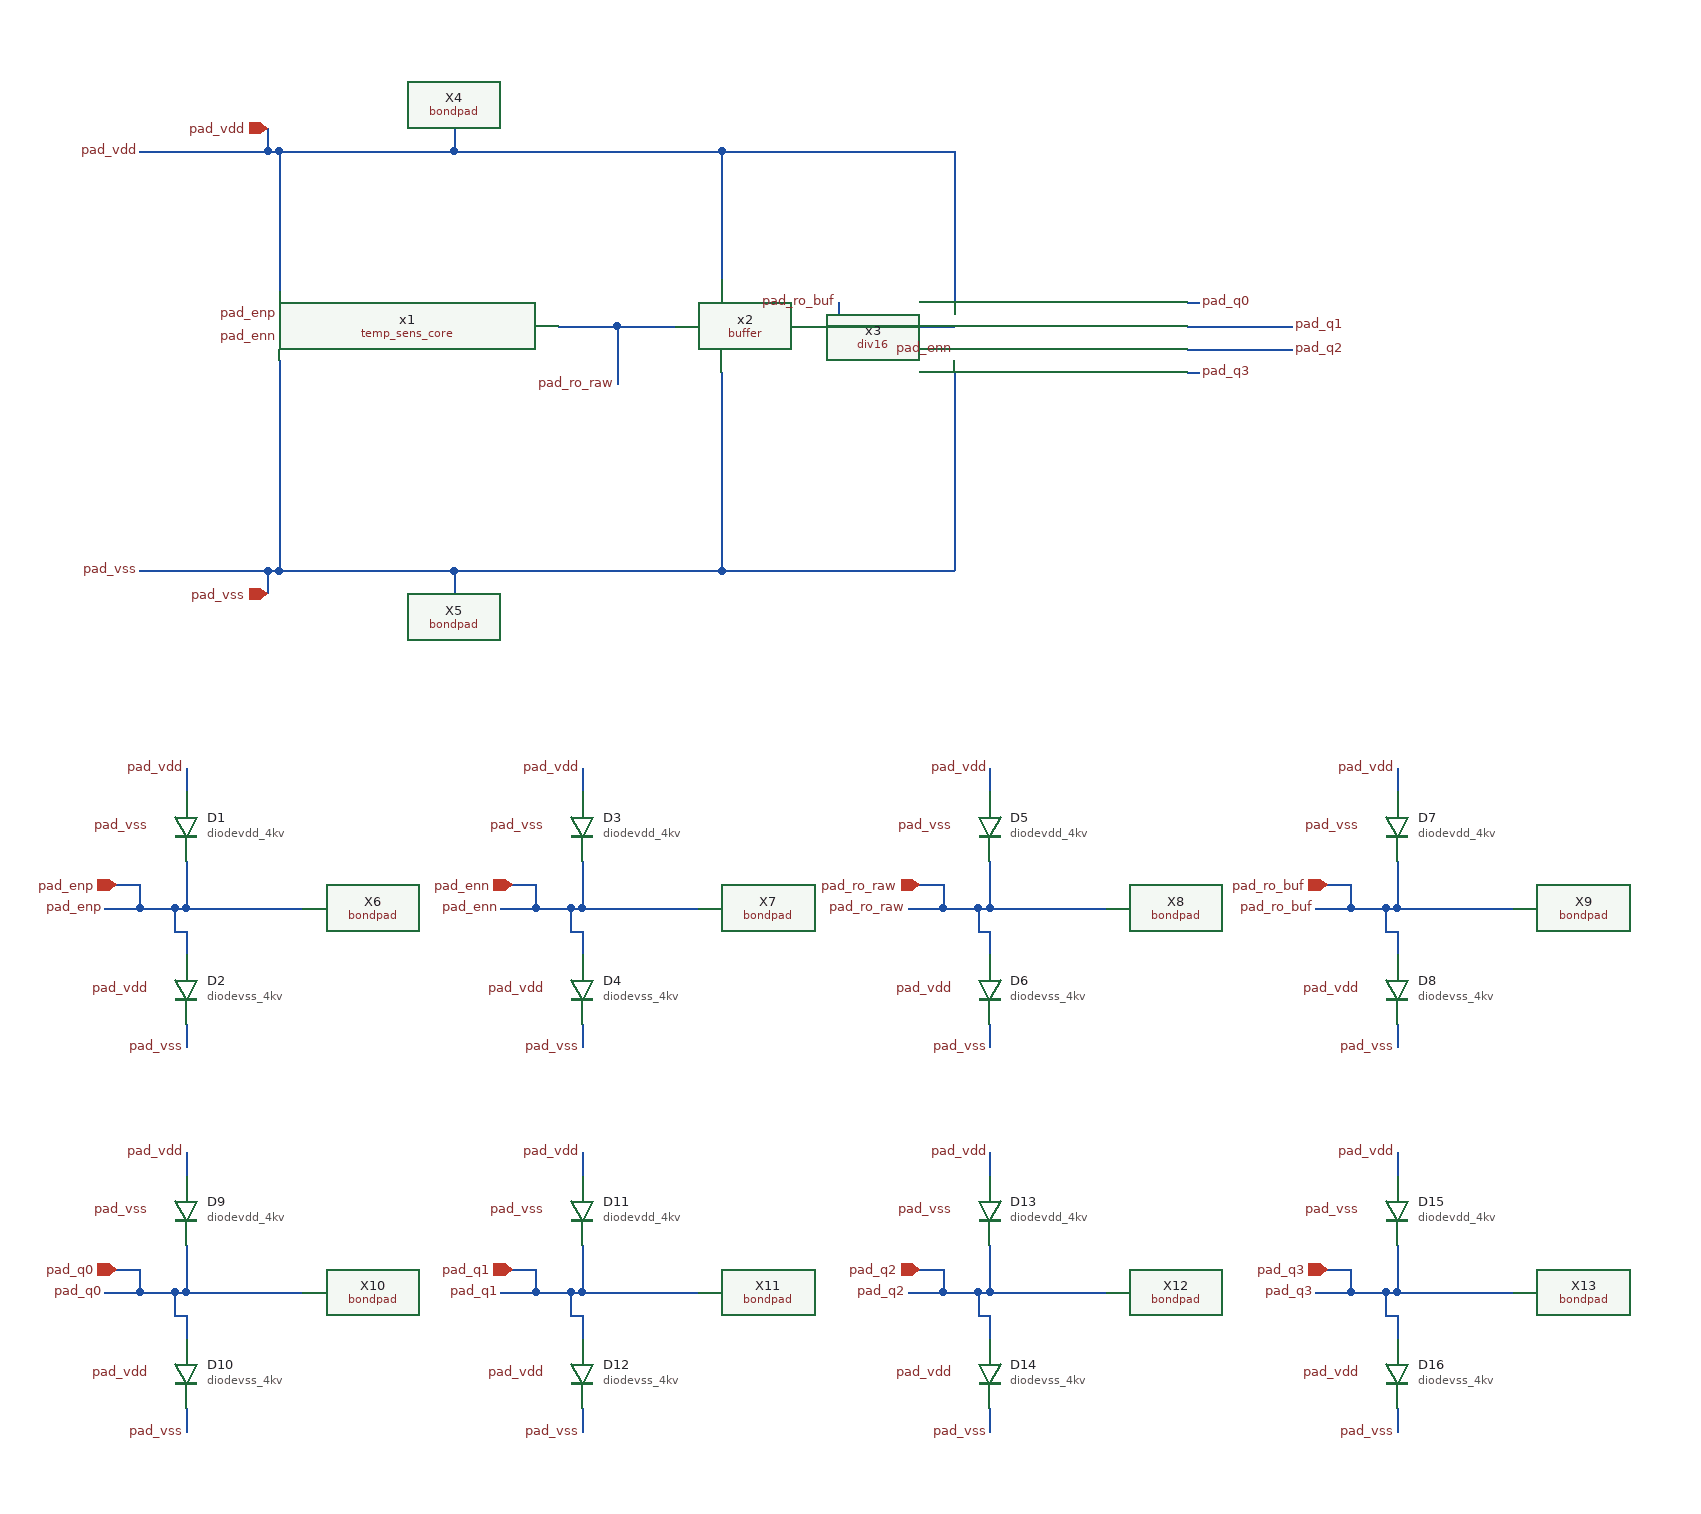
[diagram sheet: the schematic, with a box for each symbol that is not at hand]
v {xschem version=3.4.8RC file_version=1.3}
G {}
K {}
V {}
S {}
F {}
E {}
N 540 -990 590 -990 {lab=pad_ro_raw}
N 1030 -1010 1040 -1010 {lab=pad_q0}
N 1030 -950 1040 -950 {lab=pad_q3}
N 1030 -990 1120 -990 {lab=pad_q1}
N 1030 -970 1120 -970 {lab=pad_q2}
N 540 -990 540 -940 {lab=pad_ro_raw}
N 490 -990 540 -990 {lab=pad_ro_raw}
N 730 -990 830 -990 {lab=pad_ro_buf}
N 250 -1140 250 -1020 {lab=pad_vdd}
N 240 -1140 250 -1140 {lab=pad_vdd}
N 630 -1140 630 -1030 {lab=pad_vdd}
N 400 -1140 630 -1140 {lab=pad_vdd}
N 830 -1140 830 -1010 {lab=pad_vdd}
N 630 -1140 830 -1140 {lab=pad_vdd}
N 400 -780 400 -760 {lab=pad_vss}
N 250 -780 400 -780 {lab=pad_vss}
N 400 -1160 400 -1140 {lab=pad_vdd}
N 250 -1140 400 -1140 {lab=pad_vdd}
N 240 -1160 240 -1140 {lab=pad_vdd}
N 130 -1140 240 -1140 {lab=pad_vdd}
N 250 -960 250 -780 {lab=pad_vss}
N 240 -780 250 -780 {lab=pad_vss}
N 630 -950 630 -780 {lab=pad_vss}
N 400 -780 630 -780 {lab=pad_vss}
N 830 -950 830 -780 {lab=pad_vss}
N 630 -780 830 -780 {lab=pad_vss}
N 170 -490 270 -490 {lab=pad_enp}
N 170 -530 170 -490 {lab=pad_enp}
N 160 -490 170 -490 {lab=pad_enp}
N 170 -610 170 -590 {lab=pad_vdd}
N 170 -390 170 -370 {lab=pad_vss}
N 170 -470 170 -450 {lab=pad_enp}
N 160 -470 170 -470 {lab=pad_enp}
N 160 -490 160 -470 {lab=pad_enp}
N 130 -490 160 -490 {lab=pad_enp}
N 110 -510 130 -510 {lab=pad_enp}
N 130 -510 130 -490 {lab=pad_enp}
N 100 -490 130 -490 {lab=pad_enp}
N 510 -490 610 -490 {lab=pad_enn}
N 510 -530 510 -490 {lab=pad_enn}
N 500 -490 510 -490 {lab=pad_enn}
N 510 -610 510 -590 {lab=pad_vdd}
N 510 -390 510 -370 {lab=pad_vss}
N 510 -470 510 -450 {lab=pad_enn}
N 500 -470 510 -470 {lab=pad_enn}
N 500 -490 500 -470 {lab=pad_enn}
N 470 -490 500 -490 {lab=pad_enn}
N 450 -510 470 -510 {lab=pad_enn}
N 470 -510 470 -490 {lab=pad_enn}
N 440 -490 470 -490 {lab=pad_enn}
N 860 -490 960 -490 {lab=pad_ro_raw}
N 860 -530 860 -490 {lab=pad_ro_raw}
N 850 -490 860 -490 {lab=pad_ro_raw}
N 860 -610 860 -590 {lab=pad_vdd}
N 860 -390 860 -370 {lab=pad_vss}
N 860 -470 860 -450 {lab=pad_ro_raw}
N 850 -470 860 -470 {lab=pad_ro_raw}
N 850 -490 850 -470 {lab=pad_ro_raw}
N 820 -490 850 -490 {lab=pad_ro_raw}
N 800 -510 820 -510 {lab=pad_ro_raw}
N 820 -510 820 -490 {lab=pad_ro_raw}
N 790 -490 820 -490 {lab=pad_ro_raw}
N 1210 -490 1310 -490 {lab=pad_ro_buf}
N 1210 -530 1210 -490 {lab=pad_ro_buf}
N 1200 -490 1210 -490 {lab=pad_ro_buf}
N 1210 -610 1210 -590 {lab=pad_vdd}
N 1210 -390 1210 -370 {lab=pad_vss}
N 1210 -470 1210 -450 {lab=pad_ro_buf}
N 1200 -470 1210 -470 {lab=pad_ro_buf}
N 1200 -490 1200 -470 {lab=pad_ro_buf}
N 1170 -490 1200 -490 {lab=pad_ro_buf}
N 1150 -510 1170 -510 {lab=pad_ro_buf}
N 1170 -510 1170 -490 {lab=pad_ro_buf}
N 1140 -490 1170 -490 {lab=pad_ro_buf}
N 170 -160 270 -160 {lab=pad_q0}
N 170 -200 170 -160 {lab=pad_q0}
N 160 -160 170 -160 {lab=pad_q0}
N 170 -280 170 -260 {lab=pad_vdd}
N 170 -60 170 -40 {lab=pad_vss}
N 170 -140 170 -120 {lab=pad_q0}
N 160 -140 170 -140 {lab=pad_q0}
N 160 -160 160 -140 {lab=pad_q0}
N 130 -160 160 -160 {lab=pad_q0}
N 110 -180 130 -180 {lab=pad_q0}
N 130 -180 130 -160 {lab=pad_q0}
N 100 -160 130 -160 {lab=pad_q0}
N 510 -160 610 -160 {lab=pad_q1}
N 510 -200 510 -160 {lab=pad_q1}
N 500 -160 510 -160 {lab=pad_q1}
N 510 -280 510 -260 {lab=pad_vdd}
N 510 -60 510 -40 {lab=pad_vss}
N 510 -140 510 -120 {lab=pad_q1}
N 500 -140 510 -140 {lab=pad_q1}
N 500 -160 500 -140 {lab=pad_q1}
N 470 -160 500 -160 {lab=pad_q1}
N 450 -180 470 -180 {lab=pad_q1}
N 470 -180 470 -160 {lab=pad_q1}
N 440 -160 470 -160 {lab=pad_q1}
N 860 -160 960 -160 {lab=pad_q2}
N 860 -200 860 -160 {lab=pad_q2}
N 850 -160 860 -160 {lab=pad_q2}
N 860 -280 860 -260 {lab=pad_vdd}
N 860 -60 860 -40 {lab=pad_vss}
N 860 -140 860 -120 {lab=pad_q2}
N 850 -140 860 -140 {lab=pad_q2}
N 850 -160 850 -140 {lab=pad_q2}
N 820 -160 850 -160 {lab=pad_q2}
N 800 -180 820 -180 {lab=pad_q2}
N 820 -180 820 -160 {lab=pad_q2}
N 790 -160 820 -160 {lab=pad_q2}
N 1210 -160 1310 -160 {lab=pad_enp}
N 1210 -200 1210 -160 {lab=pad_enp}
N 1200 -160 1210 -160 {lab=pad_enp}
N 1210 -280 1210 -260 {lab=pad_vdd}
N 1210 -60 1210 -40 {lab=pad_vss}
N 1210 -140 1210 -120 {lab=pad_enp}
N 1200 -140 1210 -140 {lab=pad_enp}
N 1200 -160 1200 -140 {lab=pad_enp}
N 1170 -160 1200 -160 {lab=pad_enp}
N 1150 -180 1170 -180 {lab=pad_enp}
N 1170 -180 1170 -160 {lab=pad_enp}
N 1140 -160 1170 -160 {lab=pad_enp}
N 730 -1010 730 -990 {lab=pad_ro_buf}
N 690 -990 730 -990 {lab=pad_ro_buf}
N 240 -780 240 -760 {lab=pad_vss}
N 130 -780 240 -780 {lab=pad_vss}
C {TSENSE8490-main/schematic/xschem/analog/temp-sens-core/temp_sens_core.sym} 370 -1000 0 0 {name=x1 lstarv=0.46u}
C {TSENSE8490-main/schematic/xschem/analog/buffer/buffer.sym} 470 -870 0 0 {name=x2}
C {TSENSE8490-main/schematic/xschem/digital/div16/xschem/div16.sym} 930 -950 0 0 {name=x3}
C {lab_pin.sym} 100 -490 0 0 {name=p13 sig_type=std_logic lab=pad_enp
}
C {lab_pin.sym} 440 -490 0 0 {name=p14 sig_type=std_logic lab=pad_enn
}
C {lab_pin.sym} 250 -1000 0 0 {name=p19 sig_type=std_logic lab=pad_enp
}
C {lab_pin.sym} 250 -980 0 0 {name=p20 sig_type=std_logic lab=pad_enn
}
C {lab_pin.sym} 830 -970 0 0 {name=p11 sig_type=std_logic lab=pad_enn
}
C {sg13cmos5l_pr/bondpad.sym} 400 -1200 0 0 {name=X4
model=bondpad
spiceprefix=X
size=150u
shape=0
padtype=0
}
C {sg13cmos5l_pr/bondpad.sym} 400 -720 2 0 {name=X5
model=bondpad
spiceprefix=X
size=150u
shape=0
padtype=0
}
C {sg13cmos5l_pr/bondpad.sym} 270 -530 0 0 {name=X6
model=bondpad
spiceprefix=X
size=150u
shape=0
padtype=0
}
C {sg13cmos5l_pr/bondpad.sym} 610 -530 0 0 {name=X7
model=bondpad
spiceprefix=X
size=150u
shape=0
padtype=0
}
C {sg13cmos5l_pr/bondpad.sym} 960 -530 0 0 {name=X8
model=bondpad
spiceprefix=X
size=150u
shape=0
padtype=0
}
C {sg13cmos5l_pr/bondpad.sym} 1310 -530 0 0 {name=X9
model=bondpad
spiceprefix=X
size=150u
shape=0
padtype=0
}
C {sg13cmos5l_pr/bondpad.sym} 270 -200 0 0 {name=X10
model=bondpad
spiceprefix=X
size=150u
shape=0
padtype=0
}
C {sg13cmos5l_pr/bondpad.sym} 610 -200 0 0 {name=X11
model=bondpad
spiceprefix=X
size=150u
shape=0
padtype=0
}
C {sg13cmos5l_pr/bondpad.sym} 960 -200 0 0 {name=X12
model=bondpad
spiceprefix=X
size=150u
shape=0
padtype=0
}
C {sg13cmos5l_pr/bondpad.sym} 1310 -200 0 0 {name=X13
model=bondpad
spiceprefix=X
size=150u
shape=0
padtype=0
}
C {lab_pin.sym} 540 -940 3 0 {name=p1 sig_type=std_logic lab=pad_ro_raw
}
C {lab_pin.sym} 730 -1010 1 0 {name=p2 sig_type=std_logic lab=pad_ro_buf
}
C {lab_pin.sym} 1040 -1010 2 0 {name=p3 sig_type=std_logic lab=pad_q0
}
C {lab_pin.sym} 1120 -990 2 0 {name=p4 sig_type=std_logic lab=pad_q1}
C {lab_pin.sym} 1120 -970 2 0 {name=p5 sig_type=std_logic lab=pad_q2}
C {lab_pin.sym} 1040 -950 2 0 {name=p7 sig_type=std_logic lab=pad_q3}
C {iopin.sym} 240 -1160 3 0 {name=p8 lab=pad_vdd}
C {iopin.sym} 240 -760 1 0 {name=p9 lab=pad_vss}
C {iopin.sym} 110 -510 2 0 {name=p22 lab=pad_enp}
C {iopin.sym} 450 -510 2 0 {name=p23 lab=pad_enn}
C {lab_pin.sym} 790 -490 0 0 {name=p24 sig_type=std_logic lab=pad_ro_raw
}
C {iopin.sym} 800 -510 2 0 {name=p25 lab=pad_ro_raw}
C {iopin.sym} 1150 -510 2 0 {name=p30 lab=pad_ro_buf}
C {lab_pin.sym} 1140 -490 0 0 {name=p36 sig_type=std_logic lab=pad_ro_buf
}
C {sg13cmos5l_pr/diodevdd_4kv.sym} 170 -560 0 0 {name=D1
model=diodevdd_4kv
m=1
spiceprefix=X
}
C {sg13cmos5l_pr/diodevss_4kv.sym} 170 -420 0 0 {name=D2
model=diodevss_4kv
spiceprefix=X
m=1
}
C {sg13cmos5l_pr/diodevdd_4kv.sym} 510 -560 0 0 {name=D3
model=diodevdd_4kv
m=1
spiceprefix=X
}
C {sg13cmos5l_pr/diodevss_4kv.sym} 510 -420 0 0 {name=D4
model=diodevss_4kv
spiceprefix=X
m=1
}
C {sg13cmos5l_pr/diodevdd_4kv.sym} 860 -560 0 0 {name=D5
model=diodevdd_4kv
m=1
spiceprefix=X
}
C {sg13cmos5l_pr/diodevss_4kv.sym} 860 -420 0 0 {name=D6
model=diodevss_4kv
spiceprefix=X
m=1
}
C {sg13cmos5l_pr/diodevdd_4kv.sym} 1210 -560 0 0 {name=D7
model=diodevdd_4kv
m=1
spiceprefix=X
}
C {sg13cmos5l_pr/diodevss_4kv.sym} 1210 -420 0 0 {name=D8
model=diodevss_4kv
spiceprefix=X
m=1
}
C {sg13cmos5l_pr/diodevdd_4kv.sym} 170 -230 0 0 {name=D9
model=diodevdd_4kv
m=1
spiceprefix=X
}
C {sg13cmos5l_pr/diodevss_4kv.sym} 170 -90 0 0 {name=D10
model=diodevss_4kv
spiceprefix=X
m=1
}
C {sg13cmos5l_pr/diodevdd_4kv.sym} 510 -230 0 0 {name=D11
model=diodevdd_4kv
m=1
spiceprefix=X
}
C {sg13cmos5l_pr/diodevss_4kv.sym} 510 -90 0 0 {name=D12
model=diodevss_4kv
spiceprefix=X
m=1
}
C {sg13cmos5l_pr/diodevdd_4kv.sym} 860 -230 0 0 {name=D13
model=diodevdd_4kv
m=1
spiceprefix=X
}
C {sg13cmos5l_pr/diodevss_4kv.sym} 860 -90 0 0 {name=D14
model=diodevss_4kv
spiceprefix=X
m=1
}
C {sg13cmos5l_pr/diodevdd_4kv.sym} 1210 -230 0 0 {name=D15
model=diodevdd_4kv
m=1
spiceprefix=X
}
C {sg13cmos5l_pr/diodevss_4kv.sym} 1210 -90 0 0 {name=D16
model=diodevss_4kv
spiceprefix=X
m=1
}
C {lab_pin.sym} 130 -1140 0 0 {name=p16 sig_type=std_logic lab=pad_vdd
}
C {lab_pin.sym} 130 -780 0 0 {name=p17 sig_type=std_logic lab=pad_vss
}
C {lab_pin.sym} 170 -610 0 0 {name=p6 sig_type=std_logic lab=pad_vdd
}
C {lab_pin.sym} 510 -610 0 0 {name=p12 sig_type=std_logic lab=pad_vdd
}
C {lab_pin.sym} 860 -610 0 0 {name=p18 sig_type=std_logic lab=pad_vdd
}
C {lab_pin.sym} 1210 -610 0 0 {name=p34 sig_type=std_logic lab=pad_vdd
}
C {lab_pin.sym} 1180 -420 0 0 {name=p38 sig_type=std_logic lab=pad_vdd
}
C {lab_pin.sym} 830 -420 0 0 {name=p40 sig_type=std_logic lab=pad_vdd
}
C {lab_pin.sym} 480 -420 0 0 {name=p42 sig_type=std_logic lab=pad_vdd
}
C {lab_pin.sym} 140 -420 0 0 {name=p44 sig_type=std_logic lab=pad_vdd
}
C {lab_pin.sym} 170 -280 0 0 {name=p46 sig_type=std_logic lab=pad_vdd
}
C {lab_pin.sym} 510 -280 0 0 {name=p48 sig_type=std_logic lab=pad_vdd
}
C {lab_pin.sym} 860 -280 0 0 {name=p50 sig_type=std_logic lab=pad_vdd
}
C {lab_pin.sym} 1210 -280 0 0 {name=p51 sig_type=std_logic lab=pad_vdd
}
C {lab_pin.sym} 1180 -90 0 0 {name=p52 sig_type=std_logic lab=pad_vdd
}
C {lab_pin.sym} 830 -90 0 0 {name=p54 sig_type=std_logic lab=pad_vdd
}
C {lab_pin.sym} 480 -90 0 0 {name=p56 sig_type=std_logic lab=pad_vdd
}
C {lab_pin.sym} 140 -90 0 0 {name=p57 sig_type=std_logic lab=pad_vdd
}
C {lab_pin.sym} 140 -560 0 0 {name=p10 sig_type=std_logic lab=pad_vss
}
C {lab_pin.sym} 170 -370 0 0 {name=p15 sig_type=std_logic lab=pad_vss
}
C {lab_pin.sym} 140 -230 0 0 {name=p21 sig_type=std_logic lab=pad_vss
}
C {lab_pin.sym} 170 -40 0 0 {name=p37 sig_type=std_logic lab=pad_vss
}
C {lab_pin.sym} 510 -40 0 0 {name=p39 sig_type=std_logic lab=pad_vss
}
C {lab_pin.sym} 480 -230 0 0 {name=p41 sig_type=std_logic lab=pad_vss
}
C {lab_pin.sym} 830 -230 0 0 {name=p43 sig_type=std_logic lab=pad_vss
}
C {lab_pin.sym} 860 -40 0 0 {name=p45 sig_type=std_logic lab=pad_vss
}
C {lab_pin.sym} 1210 -40 0 0 {name=p47 sig_type=std_logic lab=pad_vss
}
C {lab_pin.sym} 1180 -230 0 0 {name=p49 sig_type=std_logic lab=pad_vss
}
C {lab_pin.sym} 1210 -370 0 0 {name=p53 sig_type=std_logic lab=pad_vss
}
C {lab_pin.sym} 1180 -560 0 0 {name=p55 sig_type=std_logic lab=pad_vss
}
C {lab_pin.sym} 830 -560 0 0 {name=p58 sig_type=std_logic lab=pad_vss
}
C {lab_pin.sym} 860 -370 0 0 {name=p59 sig_type=std_logic lab=pad_vss
}
C {lab_pin.sym} 480 -560 0 0 {name=p60 sig_type=std_logic lab=pad_vss
}
C {lab_pin.sym} 510 -370 0 0 {name=p61 sig_type=std_logic lab=pad_vss
}
C {iopin.sym} 110 -180 2 0 {name=p26 lab=pad_q0}
C {iopin.sym} 450 -180 2 0 {name=p27 lab=pad_q1}
C {iopin.sym} 800 -180 2 0 {name=p28 lab=pad_q2}
C {iopin.sym} 1150 -180 2 0 {name=p29 lab=pad_q3}
C {lab_pin.sym} 100 -160 0 0 {name=p31 sig_type=std_logic lab=pad_q0
}
C {lab_pin.sym} 440 -160 0 0 {name=p32 sig_type=std_logic lab=pad_q1}
C {lab_pin.sym} 790 -160 0 0 {name=p33 sig_type=std_logic lab=pad_q2}
C {lab_pin.sym} 1140 -160 0 0 {name=p35 sig_type=std_logic lab=pad_q3}
